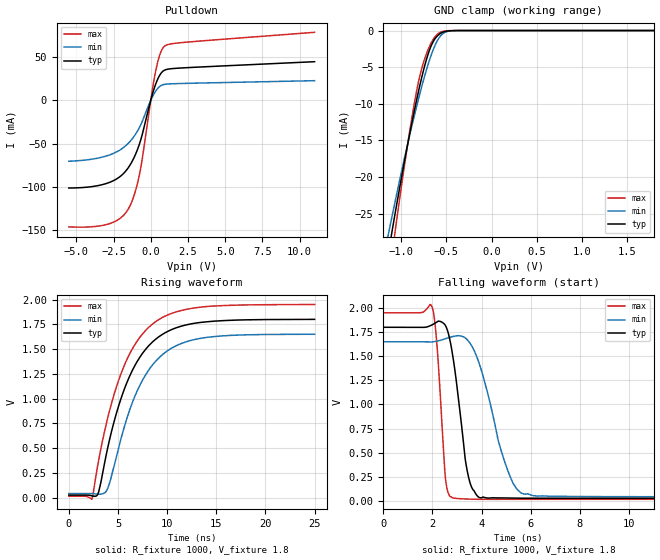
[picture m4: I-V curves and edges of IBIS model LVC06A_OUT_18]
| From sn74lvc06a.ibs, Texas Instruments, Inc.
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[Model]   LVC06A_OUT_18
Model_type  Open_drain
Enable   Active-Low
Vref =   3.6
Rref =   1000
Cref =   30p
Vmeas =   0.9
| variable   typ   min   max
C_comp   2.70pF   2.24pF   3.13pF
| C_pulldown   6.46pF   3.29pF   9.76pF
| C_tri-state   2.70pF   2.24pF   3.13pF
[Temperature Range]   40   100   -40
| Ambient temperature   25   85   -40
[Voltage range]   1.8   1.65   1.95
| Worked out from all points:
|   slope of the pulldown table from 0 to 0.27 V, typ, clamps not added: 17.1 ohm
|   GND clamp passes 1 mA (typ) near -0.62 V on its own axis
|   rising waveform, R_fixture 1000, V_fixture 1.8: 20-80 % time 3.71ns typ, 3.71ns min, 3.75ns max; typ from 0.027 V to 1.8 V
|   falling waveform, R_fixture 1000, V_fixture 1.8: 20-80 % time 505ps typ, 977ps min, 281ps max; typ from 1.8 V to 0.027 V
[GND Clamp]
| LVC06A_OUT_18
|   Voltage   I(typ)   I(min)   I(max)
-5.5V     -457.6mA   -381.7mA   -564.5mA
-1.135V   -29.64mA   -27.2mA    -33.42mA
-1.1V     -27.1mA    -25.1mA    -30.16mA
-1.065V   -24.61mA   -23.04mA   -26.98mA
-910mV    -14.22mA   -14.38mA   -13.88mA
-810mV    -8.275mA   -9.302mA   -6.974mA
-755mV    -5.424mA   -6.761mA   -4.348mA
-695mV    -2.89mA    -4.283mA   -2.34mA
-595mV    -660.3uA   -1.249mA   -450.2uA
-515mV    -133.1uA   -242.3uA   -56.19uA
-380mV    -4.005uA   -8.196uA   -499.6nA
1.8V      36.92pA    176pA      18.06pA
[Pulldown]
| LVC06A_OUT_18
|   Voltage   I(typ)   I(min)   I(max)
-5.5V     -101.5mA   -70.49mA   -146.5mA
-2.765V   -94.94mA   -63.19mA   -142.7mA
-1.98V    -87.11mA   -56.52mA   -135.6mA
-1.445V   -76.36mA   -48.57mA   -123.8mA
-1.06V    -63.97mA   -40.17mA   -106.9mA
-720mV    -48.43mA   -30.11mA   -82.62mA
100mV     6.332mA    3.683mA    11.45mA
380mV     20.98mA    11.92mA    37.85mA
655mV     30.52mA    16.76mA    55.04mA
930mV     34.99mA    18.54mA    62.77mA
2.165V    37.62mA    19.6mA     67.03mA
11V       44.79mA    22.8mA     78.8mA
[Ramp]
| LVC06A_OUT_18
| variable   typ   min   max
dV/dt_r   1.07/3.73E-09   0.97/3.72E-09   1.18/3.77E-09
dV/dt_f   1.10/5.46E-10   1.00/1.09E-09   1.21/3.03E-10
R_load = 1000
[Rising Waveform]
| LVC06A_OUT_18
R_fixture =   1000
C_fixture =   0
L_fixture =   0
V_fixture =   1.8
V_fixture_min = 1.65
V_fixture_max = 1.95
|   Time   V(typ)   V(min)   V(max)
0s        27.13mV    42.42mV    16.27mV
2.345ns   19.97mV    42.17mV    -11.87mV
2.99ns    46.62mV    35.82mV    353.8mV
3.795ns   428.4mV    64.92mV    738.5mV
4.825ns   846.8mV    407.9mV    1.113V
5.965ns   1.176V     819.4mV    1.407V
7.215ns   1.417V     1.133V     1.617V
8.61ns    1.581V     1.352V     1.76V
13.31ns   1.768V     1.607V     1.922V
24.99ns   1.8V       1.65V      1.95V
[Falling Waveform]
| LVC06A_OUT_18
R_fixture =   1000
C_fixture =   0
L_fixture =   0
V_fixture =   1.8
V_fixture_min = 1.65
V_fixture_max = 1.95
|   Time   V(typ)   V(min)   V(max)
0s        1.8V       1.65V      1.95V
1.99ns    1.826V     1.649V     2.005V
2.19ns    1.856V     1.657V     1.594V
2.535ns   1.815V     1.682V     224.7mV
2.84ns    1.483V     1.704V     29.59mV
3.335ns   432.3mV    1.691V     19.56mV
3.615ns   131.4mV    1.599V     17.33mV
4.985ns   29.75mV    374.5mV    15.97mV
5.7ns     27.61mV    72.51mV    16.17mV
24.99ns   27.13mV    42.42mV    16.27mV
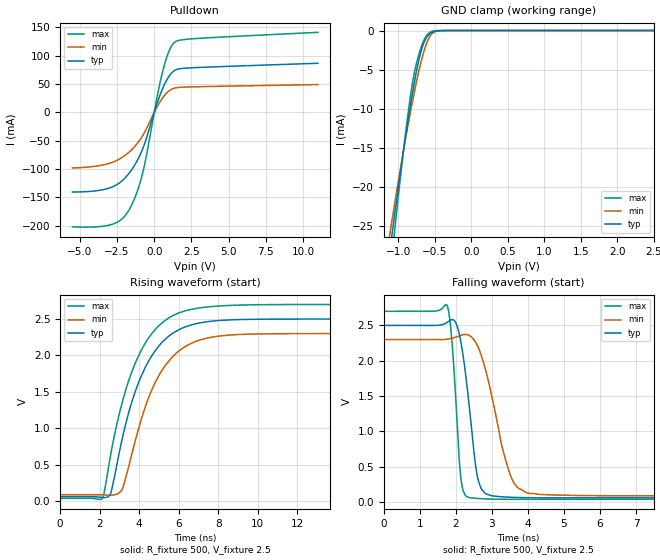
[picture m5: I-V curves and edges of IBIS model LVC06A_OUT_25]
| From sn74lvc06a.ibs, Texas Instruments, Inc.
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[Model]   LVC06A_OUT_25
Model_type  Open_drain
Enable   Active-Low
Vref =   5
Rref =   500
Cref =   30p
Vmeas =   1.25
| variable   typ   min   max
C_comp   2.61pF   2.12pF   3.15pF
| C_pulldown   6.08pF   3.10pF   8.90pF
| C_tri-state   2.61pF   2.12pF   3.15pF
[Temperature Range]   40   100   -40
| Ambient temperature   25   85   -40
[Voltage range]   2.5   2.3   2.7
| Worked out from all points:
|   slope of the pulldown table from 0 to 0.375 V, typ, clamps not added: 12.7 ohm
|   GND clamp passes 1 mA (typ) near -0.62 V on its own axis
|   rising waveform, R_fixture 500, V_fixture 2.5: 20-80 % time 1.77ns typ, 1.79ns min, 1.79ns max; typ from 0.057 V to 2.5 V
|   falling waveform, R_fixture 500, V_fixture 2.5: 20-80 % time 321ps typ, 587ps min, 189ps max; typ from 2.5 V to 0.057 V
[GND Clamp]
| LVC06A_OUT_25
|   Voltage   I(typ)   I(min)   I(max)
-5.5V     -457.6mA   -381.7mA   -564.5mA
-1.12V    -28.55mA   -26.3mA    -32.02mA
-1.08V    -25.67mA   -23.92mA   -28.33mA
-1.045V   -23.2mA    -21.88mA   -25.19mA
-890mV    -12.97mA   -13.32mA   -12.35mA
-790mV    -7.195mA   -8.353mA   -5.903mA
-680mV    -2.39mA    -3.726mA   -1.939mA
-630mV    -1.168mA   -2.109mA   -900.1uA
-570mV    -420.2uA   -796.5uA   -252uA
-495mV    -83.45uA   -150.1uA   -30.52uA
-325mV    -774nA     -1.913uA   -52.77nA
2.5V      49.44pA    204pA      25.1pA
[Pulldown]
| LVC06A_OUT_25
|   Voltage   I(typ)   I(min)   I(max)
-5.5V     -140.6mA   -98.16mA   -202mA
-2.82V    -131.6mA   -88.22mA   -197.5mA
-2.16V    -120.8mA   -79.54mA   -187.9mA
-1.64V    -105.8mA   -68.95mA   -169.6mA
-1.155V   -85.66mA   -55.27mA   -140.4mA
-735mV    -61.43mA   -39.27mA   -102.6mA
225mV     18.4mA     11.29mA    31.73mA
640mV     46.48mA    28.12mA    79.56mA
1.01V     64.3mA     38.12mA    109.2mA
1.355V    73.66mA    42.66mA    123.3mA
2.625V    78.73mA    44.97mA    129.9mA
11V       86.54mA    48.96mA    141.1mA
[Ramp]
| LVC06A_OUT_25
| variable   typ   min   max
dV/dt_r   1.47/1.78E-09   1.33/1.82E-09   1.61/1.83E-09
dV/dt_f   1.51/3.41E-10   1.37/6.25E-10   1.66/2.00E-10
R_load = 500
[Rising Waveform]
| LVC06A_OUT_25
R_fixture =   500
C_fixture =   0
L_fixture =   0
V_fixture =   2.5
V_fixture_min = 2.3
V_fixture_max = 2.7
|   Time   V(typ)   V(min)   V(max)
0s        57.33mV    84.96mV    35.94mV
2.145ns   47.07mV    83.17mV    38.31mV
2.555ns   99.2mV     78.28mV    629mV
3.11ns    812.5mV    141.5mV    1.319V
3.67ns    1.393V     685.4mV    1.802V
4.36ns    1.861V     1.33V      2.191V
5.12ns    2.168V     1.778V     2.438V
5.995ns   2.35V      2.056V     2.582V
8.955ns   2.492V     2.286V     2.691V
24.99ns   2.5V       2.3V       2.7V
[Falling Waveform]
| LVC06A_OUT_25
R_fixture =   500
C_fixture =   0
L_fixture =   0
V_fixture =   2.5
V_fixture_min = 2.3
V_fixture_max = 2.7
|   Time   V(typ)   V(min)   V(max)
0s        2.5V       2.3V       2.7V
1.755ns   2.542V     2.305V     2.784V
1.89ns    2.581V     2.317V     2.292V
2.135ns   2.28V      2.357V     364.9mV
2.38ns    1.316V     2.357V     59.71mV
2.56ns    473.2mV    2.251V     49.91mV
2.725ns   171.4mV    2.045V     44.07mV
3.505ns   65.35mV    390.2mV    35.96mV
4.035ns   58.87mV    120.5mV    35.73mV
24.99ns   57.33mV    84.96mV    35.94mV
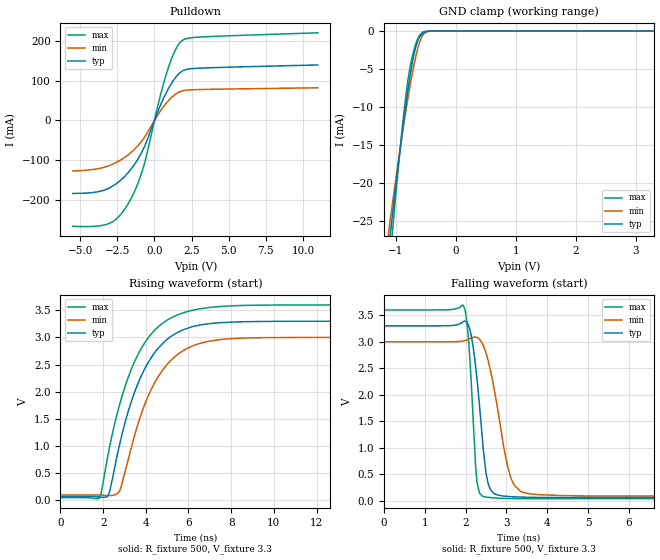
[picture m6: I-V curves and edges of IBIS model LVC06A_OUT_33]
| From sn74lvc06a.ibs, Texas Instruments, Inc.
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[Model]   LVC06A_OUT_33
Model_type  Open_drain
Enable   Active-Low
Vref =   6
Rref =   500
Cref =   50p
Vmeas =   1.5
| variable   typ   min   max
C_comp   2.53pF   2.05pF   3.14pF
| C_pulldown   5.54pF   2.95pF   7.96pF
| C_tri-state   2.53pF   2.05pF   3.14pF
[Temperature Range]   40   100   -40
| Ambient temperature   25   85   -40
[Voltage range]   3.3   3   3.6
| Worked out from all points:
|   slope of the pulldown table from 0 to 0.495 V, typ, clamps not added: 10.7 ohm
|   GND clamp passes 1 mA (typ) near -0.62 V on its own axis
|   rising waveform, R_fixture 500, V_fixture 3.3: 20-80 % time 1.7ns typ, 1.7ns min, 1.74ns max; typ from 0.065 V to 3.3 V
|   falling waveform, R_fixture 500, V_fixture 3.3: 20-80 % time 243ps typ, 407ps min, 153ps max; typ from 3.3 V to 0.065 V
[GND Clamp]
| LVC06A_OUT_33
|   Voltage   I(typ)   I(min)   I(max)
-5.5V     -457.6mA   -381.7mA   -564.5mA
-1.115V   -28.18mA   -26mA      -31.55mA
-1.08V    -25.67mA   -23.92mA   -28.33mA
-1.06V    -24.25mA   -22.75mA   -26.53mA
-1.04V    -22.86mA   -21.59mA   -24.74mA
-885mV    -12.66mA   -13.06mA   -11.98mA
-795mV    -7.461mA   -8.588mA   -6.158mA
-685mV    -2.55mA    -3.908mA   -2.068mA
-635mV    -1.261mA   -2.252mA   -982.7uA
-575mV    -461.6uA   -876uA     -284.6uA
-420mV    -12.26uA   -22.95uA   -2.327uA
3.3V      65.12pA    238.3pA    33.16pA
[Pulldown]
| LVC06A_OUT_33
|   Voltage   I(typ)   I(min)   I(max)
-5.5V     -184.5mA   -127.5mA   -267.7mA
-3.065V   -171.1mA   -114.3mA   -260.8mA
-2.41V    -155.2mA   -102.8mA   -243.5mA
-1.76V    -131.5mA   -86.55mA   -210.1mA
-1.205V   -103.4mA   -67.54mA   -167.7mA
-740mV    -71.49mA   -46.34mA   -117.7mA
350mV     33.54mA    21.13mA    56.28mA
910mV     78.57mA    48.91mA    130.7mA
1.405V    108.2mA    66.2mA     178.4mA
1.835V    124.3mA    74.47mA    201.6mA
3.11V     132.6mA    78.38mA    211.3mA
11V       140.6mA    82.78mA    221.9mA
[Ramp]
| LVC06A_OUT_33
| variable   typ   min   max
dV/dt_r   1.95/1.73E-09   1.75/1.72E-09   2.15/1.74E-09
dV/dt_f   2.00/2.58E-10   1.80/4.30E-10   2.19/1.62E-10
R_load = 500
[Rising Waveform]
| LVC06A_OUT_33
R_fixture =   500
C_fixture =   0
L_fixture =   0
V_fixture =   3.3
V_fixture_min = 3
V_fixture_max = 3.6
|   Time   V(typ)   V(min)   V(max)
0s        64.52mV    92.1mV     41.93mV
1.825ns   52.98mV    90.14mV    36.46mV
2.265ns   108.5mV    79.24mV    903.8mV
2.735ns   959.2mV    145.4mV    1.706V
3.325ns   1.82V      971.1mV    2.416V
3.965ns   2.433V     1.779V     2.91V
4.68ns    2.844V     2.335V     3.23V
5.625ns   3.119V     2.725V     3.437V
8.58ns    3.29V      2.988V     3.591V
24.99ns   3.3V       3V         3.6V
[Falling Waveform]
| LVC06A_OUT_33
R_fixture =   500
C_fixture =   0
L_fixture =   0
V_fixture =   3.3
V_fixture_min = 3
V_fixture_max = 3.6
|   Time   V(typ)   V(min)   V(max)
0s        3.3V       3V         3.6V
1.95ns    3.382V     3.018V     3.671V
2.01ns    3.381V     3.029V     3.491V
2.075ns   3.301V     3.047V     2.993V
2.275ns   2.319V     3.082V     394.8mV
2.48ns    649.8mV    2.834V     74.42mV
2.63ns    191.9mV    2.382V     60.52mV
3.09ns    81.42mV    480.6mV    44.01mV
3.57ns    67.97mV    132.2mV    41.73mV
24.99ns   64.52mV    92.1mV     41.93mV
